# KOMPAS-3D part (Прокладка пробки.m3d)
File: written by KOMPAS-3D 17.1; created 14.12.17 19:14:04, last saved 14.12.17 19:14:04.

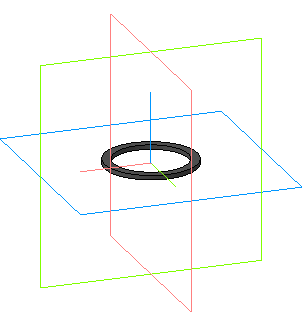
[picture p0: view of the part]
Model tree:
1. Операция без истории:1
